# Generated by innovus_enablement/scripts/gen_innovus_lef.py from ../i3dPDK_NS3K/TECH/i3dPDK_NS3K_5T_mw.tf
# i3dPDK_NS3K v1.1 (CC BY-NC-SA 4.0, Prof. Taigon Song, I3D VLSI Lab, KNU)
# NOT part of the original PDK. Directions and R/C are
# assumptions (see gen_innovus_lef.py ASSUMPTIONS).
VERSION 5.8 ;
BUSBITCHARS "[]" ;
DIVIDERCHAR "/" ;

UNITS
  DATABASE MICRONS 2000 ;
END UNITS
MANUFACTURINGGRID 0.0005 ;

SITE i3d_nsfet3nm
  CLASS CORE ;
  SYMMETRY Y ;
  SIZE 0.176 BY 0.48 ;
END i3d_nsfet3nm

SITE i3d_nsfet3nm_2H_VDD
  CLASS CORE ;
  SYMMETRY Y ;
  SIZE 0.176 BY 0.96 ;
END i3d_nsfet3nm_2H_VDD

SITE i3d_nsfet3nm_2H_VSS
  CLASS CORE ;
  SYMMETRY Y ;
  SIZE 0.176 BY 0.96 ;
END i3d_nsfet3nm_2H_VSS

SITE i3d_nsfet3nm_3H_VDD
  CLASS CORE ;
  SYMMETRY Y ;
  SIZE 0.176 BY 1.44 ;
END i3d_nsfet3nm_3H_VDD

SITE i3d_nsfet3nm_3H_VSS
  CLASS CORE ;
  SYMMETRY Y ;
  SIZE 0.176 BY 1.44 ;
END i3d_nsfet3nm_3H_VSS

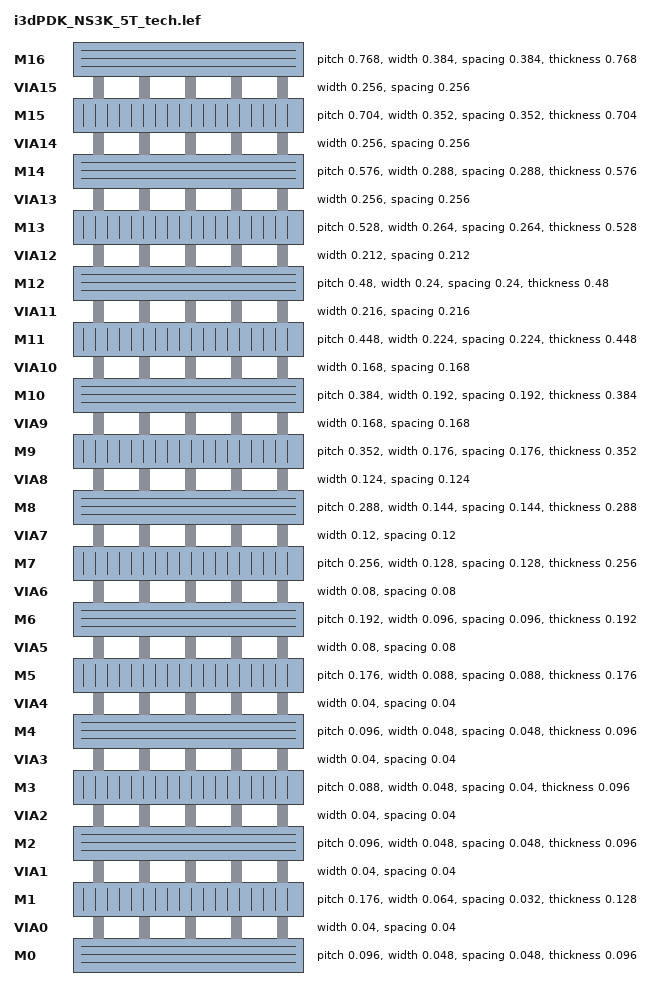
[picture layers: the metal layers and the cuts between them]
LAYER M0
  TYPE ROUTING ;
  DIRECTION HORIZONTAL ;
  PITCH 0.096 ;
  OFFSET 0.048 ;
  WIDTH 0.048 ;
  MINWIDTH 0.048 ;
  HEIGHT 0 ;
  THICKNESS 0.096 ;
  MAXWIDTH 20 ;
  SPACING 0.048 ;
  AREA 0.002304 ;
  RESISTANCE RPERSQ 8.0000 ;
  CAPACITANCE CPERSQDIST 0.00018750 ;
  EDGECAPACITANCE 0.00002000 ;
END M0

LAYER VIA0
  TYPE CUT ;
  WIDTH 0.04 ;
  SPACING 0.04 ;
  RESISTANCE 50.0000 ;
END VIA0

LAYER M1
  TYPE ROUTING ;
  DIRECTION VERTICAL ;
  PITCH 0.176 ;
  OFFSET 0.088 ;
  WIDTH 0.064 ;
  MINWIDTH 0.064 ;
  HEIGHT 0.192 ;
  THICKNESS 0.128 ;
  MAXWIDTH 20 ;
  SPACING 0.032 ;
  AREA 0.004096 ;
  RESISTANCE RPERSQ 8.0000 ;
  CAPACITANCE CPERSQDIST 0.00018750 ;
  EDGECAPACITANCE 0.00002000 ;
END M1

LAYER VIA1
  TYPE CUT ;
  WIDTH 0.04 ;
  SPACING 0.04 ;
  RESISTANCE 50.0000 ;
END VIA1

LAYER M2
  TYPE ROUTING ;
  DIRECTION HORIZONTAL ;
  PITCH 0.096 ;
  OFFSET 0.048 ;
  WIDTH 0.048 ;
  MINWIDTH 0.048 ;
  HEIGHT 0.448 ;
  THICKNESS 0.096 ;
  MAXWIDTH 20 ;
  SPACING 0.048 ;
  AREA 0.002304 ;
  RESISTANCE RPERSQ 8.0000 ;
  CAPACITANCE CPERSQDIST 0.00018750 ;
  EDGECAPACITANCE 0.00002000 ;
END M2

LAYER VIA2
  TYPE CUT ;
  WIDTH 0.04 ;
  SPACING 0.04 ;
  RESISTANCE 50.0000 ;
END VIA2

LAYER M3
  TYPE ROUTING ;
  DIRECTION VERTICAL ;
  PITCH 0.088 ;
  OFFSET 0.044 ;
  WIDTH 0.048 ;
  MINWIDTH 0.048 ;
  HEIGHT 0.64 ;
  THICKNESS 0.096 ;
  MAXWIDTH 20 ;
  SPACING 0.04 ;
  AREA 0.002304 ;
  RESISTANCE RPERSQ 8.0000 ;
  CAPACITANCE CPERSQDIST 0.00018750 ;
  EDGECAPACITANCE 0.00002000 ;
END M3

LAYER VIA3
  TYPE CUT ;
  WIDTH 0.04 ;
  SPACING 0.04 ;
  RESISTANCE 50.0000 ;
END VIA3

LAYER M4
  TYPE ROUTING ;
  DIRECTION HORIZONTAL ;
  PITCH 0.096 ;
  OFFSET 0.048 ;
  WIDTH 0.048 ;
  MINWIDTH 0.048 ;
  HEIGHT 0.832 ;
  THICKNESS 0.096 ;
  MAXWIDTH 20 ;
  SPACING 0.048 ;
  AREA 0.002304 ;
  RESISTANCE RPERSQ 1.2000 ;
  CAPACITANCE CPERSQDIST 0.00012500 ;
  EDGECAPACITANCE 0.00001750 ;
END M4

LAYER VIA4
  TYPE CUT ;
  WIDTH 0.04 ;
  SPACING 0.04 ;
  RESISTANCE 15.0000 ;
END VIA4

LAYER M5
  TYPE ROUTING ;
  DIRECTION VERTICAL ;
  PITCH 0.176 ;
  OFFSET 0.088 ;
  WIDTH 0.088 ;
  MINWIDTH 0.088 ;
  HEIGHT 1.024 ;
  THICKNESS 0.176 ;
  MAXWIDTH 20 ;
  SPACING 0.088 ;
  AREA 0.007744 ;
  RESISTANCE RPERSQ 1.2000 ;
  CAPACITANCE CPERSQDIST 0.00012500 ;
  EDGECAPACITANCE 0.00001750 ;
END M5

LAYER VIA5
  TYPE CUT ;
  WIDTH 0.08 ;
  SPACING 0.08 ;
  RESISTANCE 15.0000 ;
END VIA5

LAYER M6
  TYPE ROUTING ;
  DIRECTION HORIZONTAL ;
  PITCH 0.192 ;
  OFFSET 0.096 ;
  WIDTH 0.096 ;
  MINWIDTH 0.096 ;
  HEIGHT 1.376 ;
  THICKNESS 0.192 ;
  MAXWIDTH 20 ;
  SPACING 0.096 ;
  AREA 0.009216 ;
  RESISTANCE RPERSQ 1.2000 ;
  CAPACITANCE CPERSQDIST 0.00012500 ;
  EDGECAPACITANCE 0.00001750 ;
END M6

LAYER VIA6
  TYPE CUT ;
  WIDTH 0.08 ;
  SPACING 0.08 ;
  RESISTANCE 15.0000 ;
END VIA6

LAYER M7
  TYPE ROUTING ;
  DIRECTION VERTICAL ;
  PITCH 0.256 ;
  OFFSET 0.128 ;
  WIDTH 0.128 ;
  MINWIDTH 0.128 ;
  HEIGHT 1.76 ;
  THICKNESS 0.256 ;
  MAXWIDTH 20 ;
  SPACING 0.128 ;
  AREA 0.016384 ;
  RESISTANCE RPERSQ 1.2000 ;
  CAPACITANCE CPERSQDIST 0.00012500 ;
  EDGECAPACITANCE 0.00001750 ;
END M7

LAYER VIA7
  TYPE CUT ;
  WIDTH 0.12 ;
  SPACING 0.12 ;
  RESISTANCE 15.0000 ;
END VIA7

LAYER M8
  TYPE ROUTING ;
  DIRECTION HORIZONTAL ;
  PITCH 0.288 ;
  OFFSET 0.144 ;
  WIDTH 0.144 ;
  MINWIDTH 0.144 ;
  HEIGHT 2.272 ;
  THICKNESS 0.288 ;
  MAXWIDTH 20 ;
  SPACING 0.144 ;
  AREA 0.020736 ;
  RESISTANCE RPERSQ 1.0000 ;
  CAPACITANCE CPERSQDIST 0.00012500 ;
  EDGECAPACITANCE 0.00001750 ;
END M8

LAYER VIA8
  TYPE CUT ;
  WIDTH 0.124 ;
  SPACING 0.124 ;
  RESISTANCE 10.0000 ;
END VIA8

LAYER M9
  TYPE ROUTING ;
  DIRECTION VERTICAL ;
  PITCH 0.352 ;
  OFFSET 0.176 ;
  WIDTH 0.176 ;
  MINWIDTH 0.176 ;
  HEIGHT 2.848 ;
  THICKNESS 0.352 ;
  MAXWIDTH 20 ;
  SPACING 0.176 ;
  AREA 0.030976 ;
  RESISTANCE RPERSQ 1.0000 ;
  CAPACITANCE CPERSQDIST 0.00012500 ;
  EDGECAPACITANCE 0.00001750 ;
END M9

LAYER VIA9
  TYPE CUT ;
  WIDTH 0.168 ;
  SPACING 0.168 ;
  RESISTANCE 10.0000 ;
END VIA9

LAYER M10
  TYPE ROUTING ;
  DIRECTION HORIZONTAL ;
  PITCH 0.384 ;
  OFFSET 0.192 ;
  WIDTH 0.192 ;
  MINWIDTH 0.192 ;
  HEIGHT 3.552 ;
  THICKNESS 0.384 ;
  MAXWIDTH 20 ;
  SPACING 0.192 ;
  AREA 0.036864 ;
  RESISTANCE RPERSQ 1.0000 ;
  CAPACITANCE CPERSQDIST 0.00012500 ;
  EDGECAPACITANCE 0.00001750 ;
END M10

LAYER VIA10
  TYPE CUT ;
  WIDTH 0.168 ;
  SPACING 0.168 ;
  RESISTANCE 10.0000 ;
END VIA10

LAYER M11
  TYPE ROUTING ;
  DIRECTION VERTICAL ;
  PITCH 0.448 ;
  OFFSET 0.224 ;
  WIDTH 0.224 ;
  MINWIDTH 0.224 ;
  HEIGHT 4.32 ;
  THICKNESS 0.448 ;
  MAXWIDTH 20 ;
  SPACING 0.224 ;
  AREA 0.050176 ;
  RESISTANCE RPERSQ 1.0000 ;
  CAPACITANCE CPERSQDIST 0.00012500 ;
  EDGECAPACITANCE 0.00001750 ;
END M11

LAYER VIA11
  TYPE CUT ;
  WIDTH 0.216 ;
  SPACING 0.216 ;
  RESISTANCE 10.0000 ;
END VIA11

LAYER M12
  TYPE ROUTING ;
  DIRECTION HORIZONTAL ;
  PITCH 0.48 ;
  OFFSET 0.24 ;
  WIDTH 0.24 ;
  MINWIDTH 0.24 ;
  HEIGHT 5.216 ;
  THICKNESS 0.48 ;
  MAXWIDTH 20 ;
  SPACING 0.24 ;
  AREA 0.057600 ;
  RESISTANCE RPERSQ 0.1000 ;
  CAPACITANCE CPERSQDIST 0.00006250 ;
  EDGECAPACITANCE 0.00001500 ;
END M12

LAYER VIA12
  TYPE CUT ;
  WIDTH 0.212 ;
  SPACING 0.212 ;
  RESISTANCE 2.0000 ;
END VIA12

LAYER M13
  TYPE ROUTING ;
  DIRECTION VERTICAL ;
  PITCH 0.528 ;
  OFFSET 0.264 ;
  WIDTH 0.264 ;
  MINWIDTH 0.264 ;
  HEIGHT 6.176 ;
  THICKNESS 0.528 ;
  MAXWIDTH 20 ;
  SPACING 0.264 ;
  AREA 0.069696 ;
  RESISTANCE RPERSQ 0.1000 ;
  CAPACITANCE CPERSQDIST 0.00006250 ;
  EDGECAPACITANCE 0.00001500 ;
END M13

LAYER VIA13
  TYPE CUT ;
  WIDTH 0.256 ;
  SPACING 0.256 ;
  RESISTANCE 2.0000 ;
END VIA13

LAYER M14
  TYPE ROUTING ;
  DIRECTION HORIZONTAL ;
  PITCH 0.576 ;
  OFFSET 0.288 ;
  WIDTH 0.288 ;
  MINWIDTH 0.288 ;
  HEIGHT 7.232 ;
  THICKNESS 0.576 ;
  MAXWIDTH 20 ;
  SPACING 0.288 ;
  AREA 0.082944 ;
  RESISTANCE RPERSQ 0.1000 ;
  CAPACITANCE CPERSQDIST 0.00006250 ;
  EDGECAPACITANCE 0.00001500 ;
END M14

LAYER VIA14
  TYPE CUT ;
  WIDTH 0.256 ;
  SPACING 0.256 ;
  RESISTANCE 2.0000 ;
END VIA14

LAYER M15
  TYPE ROUTING ;
  DIRECTION VERTICAL ;
  PITCH 0.704 ;
  OFFSET 0.352 ;
  WIDTH 0.352 ;
  MINWIDTH 0.352 ;
  HEIGHT 8.384 ;
  THICKNESS 0.704 ;
  MAXWIDTH 20 ;
  SPACING 0.352 ;
  AREA 0.123904 ;
  RESISTANCE RPERSQ 0.0300 ;
  CAPACITANCE CPERSQDIST 0.00003125 ;
  EDGECAPACITANCE 0.00001250 ;
END M15

LAYER VIA15
  TYPE CUT ;
  WIDTH 0.256 ;
  SPACING 0.256 ;
  RESISTANCE 0.5000 ;
END VIA15

LAYER M16
  TYPE ROUTING ;
  DIRECTION HORIZONTAL ;
  PITCH 0.768 ;
  OFFSET 0.384 ;
  WIDTH 0.384 ;
  MINWIDTH 0.384 ;
  HEIGHT 9.792 ;
  THICKNESS 0.768 ;
  MAXWIDTH 20 ;
  SPACING 0.384 ;
  AREA 0.147456 ;
  RESISTANCE RPERSQ 0.0300 ;
  CAPACITANCE CPERSQDIST 0.00003125 ;
  EDGECAPACITANCE 0.00001250 ;
END M16

VIA VIA01 DEFAULT
  RESISTANCE 50.0000 ;
  LAYER M0 ;
    RECT -0.024 -0.024 0.024 0.024 ;
  LAYER VIA0 ;
    RECT -0.02 -0.02 0.02 0.02 ;
  LAYER M1 ;
    RECT -0.032 -0.032 0.032 0.032 ;
END VIA01

VIA VIA12 DEFAULT
  RESISTANCE 50.0000 ;
  LAYER M1 ;
    RECT -0.032 -0.032 0.032 0.032 ;
  LAYER VIA1 ;
    RECT -0.02 -0.02 0.02 0.02 ;
  LAYER M2 ;
    RECT -0.024 -0.024 0.024 0.024 ;
END VIA12

VIA VIA23 DEFAULT
  RESISTANCE 50.0000 ;
  LAYER M2 ;
    RECT -0.024 -0.024 0.024 0.024 ;
  LAYER VIA2 ;
    RECT -0.02 -0.02 0.02 0.02 ;
  LAYER M3 ;
    RECT -0.024 -0.024 0.024 0.024 ;
END VIA23

VIA VIA34 DEFAULT
  RESISTANCE 50.0000 ;
  LAYER M3 ;
    RECT -0.024 -0.024 0.024 0.024 ;
  LAYER VIA3 ;
    RECT -0.02 -0.02 0.02 0.02 ;
  LAYER M4 ;
    RECT -0.024 -0.024 0.024 0.024 ;
END VIA34

VIA VIA45 DEFAULT
  RESISTANCE 15.0000 ;
  LAYER M4 ;
    RECT -0.024 -0.024 0.024 0.024 ;
  LAYER VIA4 ;
    RECT -0.02 -0.02 0.02 0.02 ;
  LAYER M5 ;
    RECT -0.044 -0.044 0.044 0.044 ;
END VIA45

VIA VIA56 DEFAULT
  RESISTANCE 15.0000 ;
  LAYER M5 ;
    RECT -0.044 -0.044 0.044 0.044 ;
  LAYER VIA5 ;
    RECT -0.04 -0.04 0.04 0.04 ;
  LAYER M6 ;
    RECT -0.048 -0.048 0.048 0.048 ;
END VIA56

VIA VIA67 DEFAULT
  RESISTANCE 15.0000 ;
  LAYER M6 ;
    RECT -0.048 -0.048 0.048 0.048 ;
  LAYER VIA6 ;
    RECT -0.04 -0.04 0.04 0.04 ;
  LAYER M7 ;
    RECT -0.064 -0.064 0.064 0.064 ;
END VIA67

VIA VIA78 DEFAULT
  RESISTANCE 15.0000 ;
  LAYER M7 ;
    RECT -0.066 -0.066 0.066 0.066 ;
  LAYER VIA7 ;
    RECT -0.062 -0.062 0.062 0.062 ;
  LAYER M8 ;
    RECT -0.072 -0.072 0.072 0.072 ;
END VIA78

VIA VIA89 DEFAULT
  RESISTANCE 10.0000 ;
  LAYER M8 ;
    RECT -0.072 -0.072 0.072 0.072 ;
  LAYER VIA8 ;
    RECT -0.062 -0.062 0.062 0.062 ;
  LAYER M9 ;
    RECT -0.088 -0.088 0.088 0.088 ;
END VIA89

VIA VIA910 DEFAULT
  RESISTANCE 10.0000 ;
  LAYER M9 ;
    RECT -0.088 -0.088 0.088 0.088 ;
  LAYER VIA9 ;
    RECT -0.084 -0.084 0.084 0.084 ;
  LAYER M10 ;
    RECT -0.096 -0.096 0.096 0.096 ;
END VIA910

VIA VIA1011 DEFAULT
  RESISTANCE 10.0000 ;
  LAYER M10 ;
    RECT -0.096 -0.096 0.096 0.096 ;
  LAYER VIA10 ;
    RECT -0.084 -0.084 0.084 0.084 ;
  LAYER M11 ;
    RECT -0.112 -0.112 0.112 0.112 ;
END VIA1011

VIA VIA1112 DEFAULT
  RESISTANCE 10.0000 ;
  LAYER M11 ;
    RECT -0.112 -0.112 0.112 0.112 ;
  LAYER VIA11 ;
    RECT -0.106 -0.106 0.106 0.106 ;
  LAYER M12 ;
    RECT -0.12 -0.12 0.12 0.12 ;
END VIA1112

VIA via1213 DEFAULT
  RESISTANCE 2.0000 ;
  LAYER M12 ;
    RECT -0.12 -0.12 0.12 0.12 ;
  LAYER VIA12 ;
    RECT -0.106 -0.106 0.106 0.106 ;
  LAYER M13 ;
    RECT -0.132 -0.132 0.132 0.132 ;
END via1213

VIA via1314 DEFAULT
  RESISTANCE 2.0000 ;
  LAYER M13 ;
    RECT -0.132 -0.132 0.132 0.132 ;
  LAYER VIA13 ;
    RECT -0.128 -0.128 0.128 0.128 ;
  LAYER M14 ;
    RECT -0.144 -0.144 0.144 0.144 ;
END via1314

VIA via1415 DEFAULT
  RESISTANCE 2.0000 ;
  LAYER M14 ;
    RECT -0.144 -0.144 0.144 0.144 ;
  LAYER VIA14 ;
    RECT -0.128 -0.128 0.128 0.128 ;
  LAYER M15 ;
    RECT -0.176 -0.176 0.176 0.176 ;
END via1415

VIA via1516 DEFAULT
  RESISTANCE 0.5000 ;
  LAYER M15 ;
    RECT -0.176 -0.176 0.176 0.176 ;
  LAYER VIA15 ;
    RECT -0.128 -0.128 0.128 0.128 ;
  LAYER M16 ;
    RECT -0.192 -0.192 0.192 0.192 ;
END via1516

VIARULE VIA01_gen GENERATE
  LAYER M0 ;
    ENCLOSURE 0.004 0.004 ;
  LAYER M1 ;
    ENCLOSURE 0.012 0.012 ;
  LAYER VIA0 ;
    RECT -0.02 -0.02 0.02 0.02 ;
    SPACING 0.08 BY 0.08 ;
END VIA01_gen

VIARULE VIA12_gen GENERATE
  LAYER M1 ;
    ENCLOSURE 0.012 0.012 ;
  LAYER M2 ;
    ENCLOSURE 0.004 0.004 ;
  LAYER VIA1 ;
    RECT -0.02 -0.02 0.02 0.02 ;
    SPACING 0.08 BY 0.08 ;
END VIA12_gen

VIARULE VIA23_gen GENERATE
  LAYER M2 ;
    ENCLOSURE 0.004 0.004 ;
  LAYER M3 ;
    ENCLOSURE 0.004 0.004 ;
  LAYER VIA2 ;
    RECT -0.02 -0.02 0.02 0.02 ;
    SPACING 0.08 BY 0.08 ;
END VIA23_gen

VIARULE VIA34_gen GENERATE
  LAYER M3 ;
    ENCLOSURE 0.004 0.004 ;
  LAYER M4 ;
    ENCLOSURE 0.004 0.004 ;
  LAYER VIA3 ;
    RECT -0.02 -0.02 0.02 0.02 ;
    SPACING 0.08 BY 0.08 ;
END VIA34_gen

VIARULE VIA45_gen GENERATE
  LAYER M4 ;
    ENCLOSURE 0.004 0.004 ;
  LAYER M5 ;
    ENCLOSURE 0.024 0.024 ;
  LAYER VIA4 ;
    RECT -0.02 -0.02 0.02 0.02 ;
    SPACING 0.08 BY 0.08 ;
END VIA45_gen

VIARULE VIA56_gen GENERATE
  LAYER M5 ;
    ENCLOSURE 0.004 0.004 ;
  LAYER M6 ;
    ENCLOSURE 0.008 0.008 ;
  LAYER VIA5 ;
    RECT -0.04 -0.04 0.04 0.04 ;
    SPACING 0.16 BY 0.16 ;
END VIA56_gen

VIARULE VIA67_gen GENERATE
  LAYER M6 ;
    ENCLOSURE 0.008 0.008 ;
  LAYER M7 ;
    ENCLOSURE 0.024 0.024 ;
  LAYER VIA6 ;
    RECT -0.04 -0.04 0.04 0.04 ;
    SPACING 0.16 BY 0.16 ;
END VIA67_gen

VIARULE VIA78_gen GENERATE
  LAYER M7 ;
    ENCLOSURE 0.004 0.004 ;
  LAYER M8 ;
    ENCLOSURE 0.008 0.008 ;
  LAYER VIA7 ;
    RECT -0.062 -0.062 0.062 0.062 ;
    SPACING 0.248 BY 0.248 ;
END VIA78_gen

VIARULE VIA89_gen GENERATE
  LAYER M8 ;
    ENCLOSURE 0.008 0.008 ;
  LAYER M9 ;
    ENCLOSURE 0.024 0.024 ;
  LAYER VIA8 ;
    RECT -0.062 -0.062 0.062 0.062 ;
    SPACING 0.248 BY 0.248 ;
END VIA89_gen

VIARULE VIA910_gen GENERATE
  LAYER M9 ;
    ENCLOSURE 0.004 0.004 ;
  LAYER M10 ;
    ENCLOSURE 0.012 0.012 ;
  LAYER VIA9 ;
    RECT -0.084 -0.084 0.084 0.084 ;
    SPACING 0.336 BY 0.336 ;
END VIA910_gen

VIARULE VIA1011_gen GENERATE
  LAYER M10 ;
    ENCLOSURE 0.012 0.012 ;
  LAYER M11 ;
    ENCLOSURE 0.024 0.024 ;
  LAYER VIA10 ;
    RECT -0.084 -0.084 0.084 0.084 ;
    SPACING 0.336 BY 0.336 ;
END VIA1011_gen

VIARULE VIA1112_gen GENERATE
  LAYER M11 ;
    ENCLOSURE 0.004 0.004 ;
  LAYER M12 ;
    ENCLOSURE 0.012 0.012 ;
  LAYER VIA11 ;
    RECT -0.106 -0.106 0.106 0.106 ;
    SPACING 0.424 BY 0.424 ;
END VIA1112_gen

VIARULE via1213_gen GENERATE
  LAYER M12 ;
    ENCLOSURE 0.012 0.012 ;
  LAYER M13 ;
    ENCLOSURE 0.024 0.024 ;
  LAYER VIA12 ;
    RECT -0.106 -0.106 0.106 0.106 ;
    SPACING 0.424 BY 0.424 ;
END via1213_gen

VIARULE via1314_gen GENERATE
  LAYER M13 ;
    ENCLOSURE 0.004 0.004 ;
  LAYER M14 ;
    ENCLOSURE 0.016 0.016 ;
  LAYER VIA13 ;
    RECT -0.128 -0.128 0.128 0.128 ;
    SPACING 0.512 BY 0.512 ;
END via1314_gen

VIARULE via1415_gen GENERATE
  LAYER M14 ;
    ENCLOSURE 0.016 0.016 ;
  LAYER M15 ;
    ENCLOSURE 0.048 0.048 ;
  LAYER VIA14 ;
    RECT -0.128 -0.128 0.128 0.128 ;
    SPACING 0.512 BY 0.512 ;
END via1415_gen

VIARULE via1516_gen GENERATE
  LAYER M15 ;
    ENCLOSURE 0.048 0.048 ;
  LAYER M16 ;
    ENCLOSURE 0.064 0.064 ;
  LAYER VIA15 ;
    RECT -0.128 -0.128 0.128 0.128 ;
    SPACING 0.512 BY 0.512 ;
END via1516_gen

END LIBRARY
